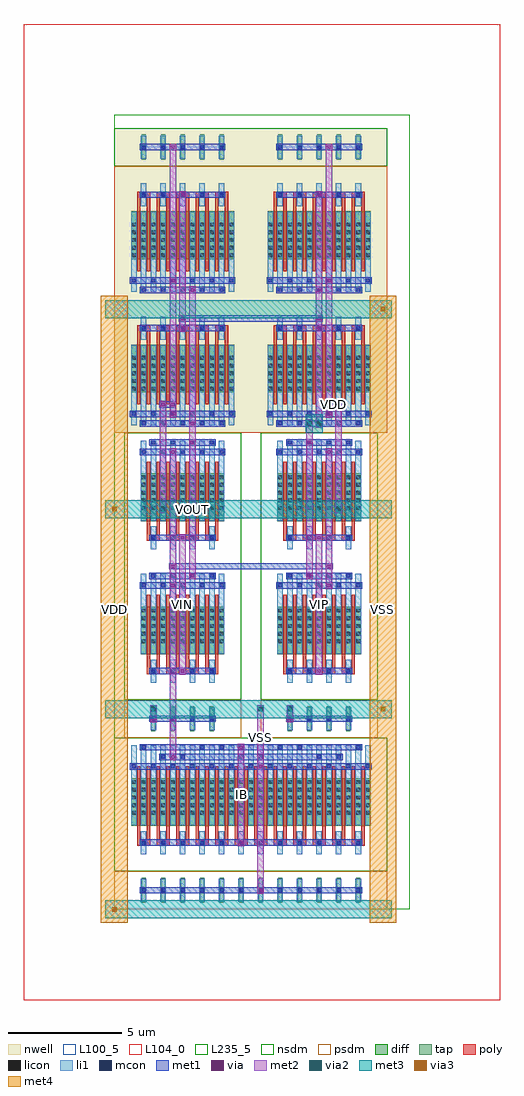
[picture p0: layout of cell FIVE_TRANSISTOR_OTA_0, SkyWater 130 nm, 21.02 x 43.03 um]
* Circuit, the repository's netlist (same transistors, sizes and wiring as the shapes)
* NGSPICE file created from FIVE_TRANSISTOR_OTA_0.ext - technology: sky130A

.subckt DCL_PMOS_S_71268420_X5_Y2_1774869003 a_200_252# w_0_0#
X0 a_200_252# a_200_252# w_0_0# w_0_0# sky130_fd_pr__pfet_01v8 ad=0.294 pd=2.38 as=0.5565 ps=4.73 w=2.1 l=0.15 M=20
.ends

.subckt NMOS_4T_52804903_X4_Y2_1774869004 a_230_357# a_200_252# a_147_357# a_241_2408#
X0 a_230_357# a_200_252# a_147_357# a_241_2408# sky130_fd_pr__nfet_01v8 ad=0.294 pd=2.38 as=0.294 ps=2.38 w=2.1 l=0.15 M=16
.ends

.subckt PMOS_S_5261831_X5_Y2_1774869005 a_230_357# a_200_252# w_0_0#
X0 a_230_357# a_200_252# w_0_0# w_0_0# sky130_fd_pr__pfet_01v8 ad=0.294 pd=2.38 as=0.5565 ps=4.73 w=2.1 l=0.15 M=20
.ends

.subckt SCM_NMOS_9937040_X6_Y1_1774869006 a_200_252# a_402_357# a_147_357#
X0 a_402_357# a_200_252# a_147_357# a_147_357# sky130_fd_pr__nfet_01v8 ad=0.294 pd=2.38 as=0.294 ps=2.38 w=2.1 l=0.15 M=12
X1 a_147_357# a_200_252# a_200_252# a_147_357# sky130_fd_pr__nfet_01v8 ad=0.5565 pd=4.73 as=0.294 ps=2.38 w=2.1 l=0.15 M=12
.ends

.subckt FIVE_TRANSISTOR_OTA_0 IB VOUT VIP VIN VSS VDD
XDCL_PMOS_S_71268420_X5_Y2_1774869003_0 m1_570_5180# VDD DCL_PMOS_S_71268420_X5_Y2_1774869003
XNMOS_4T_52804903_X4_Y2_1774869004_1 m1_570_5180# VIP m1_484_2996# VSS NMOS_4T_52804903_X4_Y2_1774869004
XNMOS_4T_52804903_X4_Y2_1774869004_0 VOUT VIN m1_484_2996# VSS NMOS_4T_52804903_X4_Y2_1774869004
XPMOS_S_5261831_X5_Y2_1774869005_0 VOUT m1_570_5180# VDD PMOS_S_5261831_X5_Y2_1774869005
XSCM_NMOS_9937040_X6_Y1_1774869006_0 IB m1_484_2996# VSS SCM_NMOS_9937040_X6_Y1_1774869006
.ends

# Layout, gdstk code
from math import pi, radians
import gdstk
lib = gdstk.Library(unit=1e-6, precision=1e-09)
def R(c, l, rs):  # rectangles x0, y0, x1, y1
    for r in rs: c.add(gdstk.rectangle(r[:2], r[2:], *l))
def A(c, l, x, y, w, h, nx, ny, dx, dy):  # array of equal rectangles
    R(c, l, [(x+i*dx, y+j*dy, x+i*dx+w, y+j*dy+h) for i in range(nx) for j in range(ny)])
def P(c, l, *ps):  # polygons
    for p in ps: c.add(gdstk.Polygon(p, *l))
nwell = (64, 20)
diff = (65, 20)
tap = (65, 44)
poly = (66, 20)
licon = (66, 44)
li1 = (67, 20)
mcon = (67, 44)
met1 = (68, 20)
via = (68, 44)
met2 = (69, 20)
via2 = (69, 44)
met3 = (70, 20)
via3 = (70, 44)
met4 = (71, 20)
nsdm = (93, 44)
psdm = (94, 20)
L100_5 = (100, 5)
L104_0 = (104, 0)
L235_5 = (235, 5)

scm_nmos_9937040_x6_y1_1 = lib.new_cell('SCM_NMOS_9937040_X6_Y1_1774869006')
R(scm_nmos_9937040_x6_y1_1, diff, [(0.735,1.785,11.305,3.885)])
A(scm_nmos_9937040_x6_y1_1, tap, 1.205, 6.16, 0.17, 1.12, 12, 1, 0.86, 0)
A(scm_nmos_9937040_x6_y1_1, poly, 1, 1.26, 0.15, 3.36, 24, 1, 0.43, 0)
A(scm_nmos_9937040_x6_y1_1, poly, 1, 4.485, 0.58, 0.27, 12, 1, 0.86, 0)
A(scm_nmos_9937040_x6_y1_1, licon, 0.775, 1.865, 0.17, 0.17, 3, 5, 0.43, 0.34)
A(scm_nmos_9937040_x6_y1_1, licon, 1.635, 1.865, 0.17, 0.17, 3, 5, 0.43, 0.34)
A(scm_nmos_9937040_x6_y1_1, licon, 2.495, 1.865, 0.17, 0.17, 3, 5, 0.43, 0.34)
A(scm_nmos_9937040_x6_y1_1, licon, 3.355, 1.865, 0.17, 0.17, 3, 5, 0.43, 0.34)
A(scm_nmos_9937040_x6_y1_1, licon, 4.215, 1.865, 0.17, 0.17, 3, 5, 0.43, 0.34)
A(scm_nmos_9937040_x6_y1_1, licon, 5.075, 1.865, 0.17, 0.17, 3, 5, 0.43, 0.34)
A(scm_nmos_9937040_x6_y1_1, licon, 5.935, 1.865, 0.17, 0.17, 3, 5, 0.43, 0.34)
A(scm_nmos_9937040_x6_y1_1, licon, 6.795, 1.865, 0.17, 0.17, 3, 5, 0.43, 0.34)
A(scm_nmos_9937040_x6_y1_1, licon, 7.655, 1.865, 0.17, 0.17, 3, 5, 0.43, 0.34)
A(scm_nmos_9937040_x6_y1_1, licon, 8.515, 1.865, 0.17, 0.17, 3, 5, 0.43, 0.34)
A(scm_nmos_9937040_x6_y1_1, licon, 9.375, 1.865, 0.17, 0.17, 3, 5, 0.43, 0.34)
A(scm_nmos_9937040_x6_y1_1, licon, 10.235, 1.865, 0.17, 0.17, 3, 5, 0.43, 0.34)
A(scm_nmos_9937040_x6_y1_1, licon, 1.205, 4.535, 0.17, 0.17, 12, 2, 0.86, 2.1)
A(scm_nmos_9937040_x6_y1_1, li1, 0.735, 0.335, 0.25, 3.53, 25, 1, 0.43, 0)
A(scm_nmos_9937040_x6_y1_1, li1, 1.165, 4.115, 0.25, 1.01, 12, 2, 0.86, 2.1)
A(scm_nmos_9937040_x6_y1_1, mcon, 0.775, 1.175, 0.17, 0.17, 13, 1, 0.86, 0)
A(scm_nmos_9937040_x6_y1_1, mcon, 1.205, 4.535, 0.17, 0.17, 12, 2, 0.86, 2.1)
R(scm_nmos_9937040_x6_y1_1, mcon, [(1.205,0.335,1.375,0.505), (3.785,0.335,3.955,0.505), (4.645,0.335,4.815,0.505), (7.225,0.335,7.395,0.505), (8.085,0.335,8.255,0.505), (10.665,0.335,10.835,0.505), (2.065,0.755,2.235,0.925), (2.925,0.755,3.095,0.925), (5.505,0.755,5.675,0.925), (6.365,0.755,6.535,0.925), (8.945,0.755,9.115,0.925), (9.805,0.755,9.975,0.925)])
R(scm_nmos_9937040_x6_y1_1, met1, [(1.12,0.28,10.92,0.56), (1.98,0.7,10.06,0.98), (0.69,1.12,11.35,1.4), (1.12,4.48,10.92,4.76), (1.12,6.58,10.92,6.86)])
R(scm_nmos_9937040_x6_y1_1, via, [(5.515,0.345,5.665,0.495), (6.375,1.185,6.525,1.335), (5.515,4.545,5.665,4.695), (6.375,6.645,6.525,6.795)])
R(scm_nmos_9937040_x6_y1_1, met2, [(5.45,0.26,5.73,4.78), (6.31,1.1,6.59,6.88)])
R(scm_nmos_9937040_x6_y1_1, nsdm, [(0,0,12.04,5.88)])
R(scm_nmos_9937040_x6_y1_1, psdm, [(0,5.88,12.04,7.56)])
R(scm_nmos_9937040_x6_y1_1, L100_5, [(0,0,12.04,7.56)])

dcl_pmos_s_71268420_x5_y = lib.new_cell('DCL_PMOS_S_71268420_X5_Y2_1774869003')
R(dcl_pmos_s_71268420_x5_y, nwell, [(0,0,6.02,13.44)])
R(dcl_pmos_s_71268420_x5_y, diff, [(0.735,1.785,5.285,3.885), (0.735,7.665,5.285,9.765)])
A(dcl_pmos_s_71268420_x5_y, tap, 1.205, 12.04, 0.17, 1.12, 5, 1, 0.86, 0)
A(dcl_pmos_s_71268420_x5_y, poly, 1, 1.26, 0.15, 3.36, 10, 2, 0.43, 5.88)
A(dcl_pmos_s_71268420_x5_y, poly, 1, 4.485, 0.58, 0.27, 5, 2, 0.86, 5.88)
A(dcl_pmos_s_71268420_x5_y, licon, 0.775, 1.865, 0.17, 0.17, 3, 5, 0.43, 0.34)
A(dcl_pmos_s_71268420_x5_y, licon, 1.635, 1.865, 0.17, 0.17, 3, 5, 0.43, 0.34)
A(dcl_pmos_s_71268420_x5_y, licon, 2.495, 1.865, 0.17, 0.17, 3, 5, 0.43, 0.34)
A(dcl_pmos_s_71268420_x5_y, licon, 3.355, 1.865, 0.17, 0.17, 3, 5, 0.43, 0.34)
A(dcl_pmos_s_71268420_x5_y, licon, 4.215, 1.865, 0.17, 0.17, 3, 5, 0.43, 0.34)
A(dcl_pmos_s_71268420_x5_y, licon, 1.205, 4.535, 0.17, 0.17, 5, 2, 0.86, 5.88)
A(dcl_pmos_s_71268420_x5_y, licon, 0.775, 7.745, 0.17, 0.17, 3, 5, 0.43, 0.34)
A(dcl_pmos_s_71268420_x5_y, licon, 1.635, 7.745, 0.17, 0.17, 3, 5, 0.43, 0.34)
A(dcl_pmos_s_71268420_x5_y, licon, 2.495, 7.745, 0.17, 0.17, 3, 5, 0.43, 0.34)
A(dcl_pmos_s_71268420_x5_y, licon, 3.355, 7.745, 0.17, 0.17, 3, 5, 0.43, 0.34)
A(dcl_pmos_s_71268420_x5_y, licon, 4.215, 7.745, 0.17, 0.17, 3, 5, 0.43, 0.34)
R(dcl_pmos_s_71268420_x5_y, licon, [(1.205,12.515,1.375,12.685), (1.205,12.515,1.375,12.685), (2.065,12.515,2.235,12.685), (2.065,12.515,2.235,12.685), (2.925,12.515,3.095,12.685), (2.925,12.515,3.095,12.685), (3.785,12.515,3.955,12.685), (3.785,12.515,3.955,12.685), (4.645,12.515,4.815,12.685), (4.645,12.515,4.815,12.685)])
A(dcl_pmos_s_71268420_x5_y, li1, 0.735, 0.335, 0.25, 3.53, 11, 2, 0.43, 5.88)
A(dcl_pmos_s_71268420_x5_y, li1, 1.165, 4.115, 0.25, 1.01, 5, 2, 0.86, 5.88)
A(dcl_pmos_s_71268420_x5_y, li1, 1.165, 12.095, 0.25, 1.01, 5, 1, 0.86, 0)
A(dcl_pmos_s_71268420_x5_y, mcon, 1.205, 0.335, 0.17, 0.17, 5, 2, 0.86, 4.2)
A(dcl_pmos_s_71268420_x5_y, mcon, 0.775, 0.755, 0.17, 0.17, 6, 2, 0.86, 5.88)
A(dcl_pmos_s_71268420_x5_y, mcon, 1.205, 6.215, 0.17, 0.17, 5, 2, 0.86, 4.2)
A(dcl_pmos_s_71268420_x5_y, mcon, 1.205, 12.515, 0.17, 0.17, 5, 1, 0.86, 0)
R(dcl_pmos_s_71268420_x5_y, met1, [(1.12,0.28,4.9,0.56), (0.69,0.7,5.33,0.98), (1.12,4.48,4.9,4.76), (1.12,6.16,4.9,6.44), (0.69,6.58,5.33,6.86), (1.12,10.36,4.9,10.64), (1.12,12.46,4.9,12.74)])
A(dcl_pmos_s_71268420_x5_y, via, 3.365, 0.765, 0.15, 0.15, 1, 3, 0, 5.88)
R(dcl_pmos_s_71268420_x5_y, via, [(2.935,0.345,3.085,0.495), (2.935,4.545,3.085,4.695), (2.935,6.225,3.085,6.375), (2.935,10.425,3.085,10.575)])
R(dcl_pmos_s_71268420_x5_y, met2, [(2.87,0.26,3.15,10.66), (3.3,0.68,3.58,12.76)])
R(dcl_pmos_s_71268420_x5_y, nsdm, [(0,11.76,6.02,13.44)])
R(dcl_pmos_s_71268420_x5_y, psdm, [(0,0,6.02,11.76)])
R(dcl_pmos_s_71268420_x5_y, L100_5, [(0,0,6.02,13.44)])

pmos_s_5261831_x5_y2_177 = lib.new_cell('PMOS_S_5261831_X5_Y2_1774869005')
R(pmos_s_5261831_x5_y2_177, nwell, [(0,0,6.02,13.44)])
R(pmos_s_5261831_x5_y2_177, diff, [(0.735,1.785,5.285,3.885), (0.735,7.665,5.285,9.765)])
A(pmos_s_5261831_x5_y2_177, tap, 1.205, 12.04, 0.17, 1.12, 5, 1, 0.86, 0)
A(pmos_s_5261831_x5_y2_177, poly, 1, 1.26, 0.15, 3.36, 10, 2, 0.43, 5.88)
A(pmos_s_5261831_x5_y2_177, poly, 1, 4.485, 0.58, 0.27, 5, 2, 0.86, 5.88)
A(pmos_s_5261831_x5_y2_177, licon, 0.775, 1.865, 0.17, 0.17, 3, 5, 0.43, 0.34)
A(pmos_s_5261831_x5_y2_177, licon, 1.635, 1.865, 0.17, 0.17, 3, 5, 0.43, 0.34)
A(pmos_s_5261831_x5_y2_177, licon, 2.495, 1.865, 0.17, 0.17, 3, 5, 0.43, 0.34)
A(pmos_s_5261831_x5_y2_177, licon, 3.355, 1.865, 0.17, 0.17, 3, 5, 0.43, 0.34)
A(pmos_s_5261831_x5_y2_177, licon, 4.215, 1.865, 0.17, 0.17, 3, 5, 0.43, 0.34)
A(pmos_s_5261831_x5_y2_177, licon, 1.205, 4.535, 0.17, 0.17, 5, 2, 0.86, 5.88)
A(pmos_s_5261831_x5_y2_177, licon, 0.775, 7.745, 0.17, 0.17, 3, 5, 0.43, 0.34)
A(pmos_s_5261831_x5_y2_177, licon, 1.635, 7.745, 0.17, 0.17, 3, 5, 0.43, 0.34)
A(pmos_s_5261831_x5_y2_177, licon, 2.495, 7.745, 0.17, 0.17, 3, 5, 0.43, 0.34)
A(pmos_s_5261831_x5_y2_177, licon, 3.355, 7.745, 0.17, 0.17, 3, 5, 0.43, 0.34)
A(pmos_s_5261831_x5_y2_177, licon, 4.215, 7.745, 0.17, 0.17, 3, 5, 0.43, 0.34)
R(pmos_s_5261831_x5_y2_177, licon, [(1.205,12.515,1.375,12.685), (1.205,12.515,1.375,12.685), (2.065,12.515,2.235,12.685), (2.065,12.515,2.235,12.685), (2.925,12.515,3.095,12.685), (2.925,12.515,3.095,12.685), (3.785,12.515,3.955,12.685), (3.785,12.515,3.955,12.685), (4.645,12.515,4.815,12.685), (4.645,12.515,4.815,12.685)])
A(pmos_s_5261831_x5_y2_177, li1, 0.735, 0.335, 0.25, 3.53, 11, 2, 0.43, 5.88)
A(pmos_s_5261831_x5_y2_177, li1, 1.165, 4.115, 0.25, 1.01, 5, 2, 0.86, 5.88)
A(pmos_s_5261831_x5_y2_177, li1, 1.165, 12.095, 0.25, 1.01, 5, 1, 0.86, 0)
A(pmos_s_5261831_x5_y2_177, mcon, 1.205, 0.335, 0.17, 0.17, 5, 2, 0.86, 4.2)
A(pmos_s_5261831_x5_y2_177, mcon, 0.775, 0.755, 0.17, 0.17, 6, 2, 0.86, 5.88)
A(pmos_s_5261831_x5_y2_177, mcon, 1.205, 6.215, 0.17, 0.17, 5, 2, 0.86, 4.2)
A(pmos_s_5261831_x5_y2_177, mcon, 1.205, 12.515, 0.17, 0.17, 5, 1, 0.86, 0)
R(pmos_s_5261831_x5_y2_177, met1, [(1.12,0.28,4.9,0.56), (0.69,0.7,5.33,0.98), (1.12,4.48,4.9,4.76), (1.12,6.16,4.9,6.44), (0.69,6.58,5.33,6.86), (1.12,10.36,4.9,10.64), (1.12,12.46,4.9,12.74)])
A(pmos_s_5261831_x5_y2_177, via, 3.365, 0.765, 0.15, 0.15, 1, 3, 0, 5.88)
R(pmos_s_5261831_x5_y2_177, via, [(2.505,0.345,2.655,0.495), (2.935,4.545,3.085,4.695), (2.505,6.225,2.655,6.375), (2.935,10.425,3.085,10.575)])
R(pmos_s_5261831_x5_y2_177, met2, [(2.44,0.26,2.72,6.46), (3.3,0.68,3.58,12.76), (2.87,4.46,3.15,10.66)])
R(pmos_s_5261831_x5_y2_177, nsdm, [(0,11.76,6.02,13.44)])
R(pmos_s_5261831_x5_y2_177, psdm, [(0,0,6.02,11.76)])
R(pmos_s_5261831_x5_y2_177, L100_5, [(0,0,6.02,13.44)])

nmos_4t_52804903_x4_y2_1 = lib.new_cell('NMOS_4T_52804903_X4_Y2_1774869004')
R(nmos_4t_52804903_x4_y2_1, diff, [(0.735,1.785,4.425,3.885), (0.735,7.665,4.425,9.765)])
A(nmos_4t_52804903_x4_y2_1, tap, 1.205, 12.04, 0.17, 1.12, 4, 1, 0.86, 0)
A(nmos_4t_52804903_x4_y2_1, poly, 1, 1.26, 0.15, 3.36, 8, 2, 0.43, 5.88)
A(nmos_4t_52804903_x4_y2_1, poly, 1, 4.485, 0.58, 0.27, 4, 2, 0.86, 5.88)
A(nmos_4t_52804903_x4_y2_1, licon, 0.775, 1.865, 0.17, 0.17, 3, 5, 0.43, 0.34)
A(nmos_4t_52804903_x4_y2_1, licon, 1.635, 1.865, 0.17, 0.17, 3, 5, 0.43, 0.34)
A(nmos_4t_52804903_x4_y2_1, licon, 2.495, 1.865, 0.17, 0.17, 3, 5, 0.43, 0.34)
A(nmos_4t_52804903_x4_y2_1, licon, 3.355, 1.865, 0.17, 0.17, 3, 5, 0.43, 0.34)
A(nmos_4t_52804903_x4_y2_1, licon, 1.205, 4.535, 0.17, 0.17, 4, 2, 0.86, 5.88)
A(nmos_4t_52804903_x4_y2_1, licon, 0.775, 7.745, 0.17, 0.17, 3, 5, 0.43, 0.34)
A(nmos_4t_52804903_x4_y2_1, licon, 1.635, 7.745, 0.17, 0.17, 3, 5, 0.43, 0.34)
A(nmos_4t_52804903_x4_y2_1, licon, 2.495, 7.745, 0.17, 0.17, 3, 5, 0.43, 0.34)
A(nmos_4t_52804903_x4_y2_1, licon, 3.355, 7.745, 0.17, 0.17, 3, 5, 0.43, 0.34)
R(nmos_4t_52804903_x4_y2_1, licon, [(1.205,12.515,1.375,12.685), (1.205,12.515,1.375,12.685), (2.065,12.515,2.235,12.685), (2.065,12.515,2.235,12.685), (2.925,12.515,3.095,12.685), (2.925,12.515,3.095,12.685), (3.785,12.515,3.955,12.685), (3.785,12.515,3.955,12.685)])
A(nmos_4t_52804903_x4_y2_1, li1, 0.735, 0.335, 0.25, 3.53, 9, 2, 0.43, 5.88)
A(nmos_4t_52804903_x4_y2_1, li1, 1.165, 4.115, 0.25, 1.01, 4, 2, 0.86, 5.88)
A(nmos_4t_52804903_x4_y2_1, li1, 1.165, 12.095, 0.25, 1.01, 4, 1, 0.86, 0)
A(nmos_4t_52804903_x4_y2_1, mcon, 1.205, 0.335, 0.17, 0.17, 4, 2, 0.86, 4.2)
A(nmos_4t_52804903_x4_y2_1, mcon, 0.775, 0.755, 0.17, 0.17, 5, 2, 0.86, 5.88)
A(nmos_4t_52804903_x4_y2_1, mcon, 1.205, 6.215, 0.17, 0.17, 4, 2, 0.86, 4.2)
A(nmos_4t_52804903_x4_y2_1, mcon, 1.205, 12.515, 0.17, 0.17, 4, 1, 0.86, 0)
R(nmos_4t_52804903_x4_y2_1, met1, [(1.12,0.28,4.04,0.56), (0.69,0.7,4.47,0.98), (1.12,4.48,4.04,4.76), (1.12,6.16,4.04,6.44), (0.69,6.58,4.47,6.86), (1.12,10.36,4.04,10.64), (1.12,12.46,4.04,12.74)])
R(nmos_4t_52804903_x4_y2_1, via, [(2.075,0.345,2.225,0.495), (2.935,0.765,3.085,0.915), (2.505,4.545,2.655,4.695), (2.075,6.225,2.225,6.375), (2.935,6.645,3.085,6.795), (2.505,10.425,2.655,10.575)])
R(nmos_4t_52804903_x4_y2_1, met2, [(2.01,0.26,2.29,6.46), (2.87,0.68,3.15,6.88), (2.44,4.46,2.72,10.66)])
R(nmos_4t_52804903_x4_y2_1, nsdm, [(0,0,5.16,11.76)])
R(nmos_4t_52804903_x4_y2_1, psdm, [(0,11.76,5.16,13.44)])
R(nmos_4t_52804903_x4_y2_1, L100_5, [(0,0,5.16,13.44)])

five_transistor_ota_0 = lib.new_cell('FIVE_TRANSISTOR_OTA_0')
R(five_transistor_ota_0, met1, [(2.42,6.58,2.74,6.86), (2.42,6.58,2.74,6.86), (2.42,6.58,2.74,6.86), (2.42,6.58,2.74,6.86), (1.56,8.26,1.88,8.54), (1.56,8.26,1.88,8.54), (7.58,8.26,7.9,8.54), (7.58,8.26,7.9,8.54), (7.58,8.26,7.9,8.54), (2.42,14.98,2.74,15.26), (2.42,14.98,2.74,15.26), (2.58,14.98,9.46,15.26), (9.3,14.98,9.62,15.26), (9.3,14.98,9.62,15.26), (1.99,22.12,2.31,22.4), (1.99,22.12,2.31,22.4), (2.15,22.12,2.58,22.4), (2.42,22.12,2.74,22.4), (2.42,22.12,2.74,22.4), (9.3,22.12,9.62,22.4), (9.3,22.12,9.62,22.4), (9.3,22.12,9.62,22.4), (9.46,22.12,9.89,22.4), (9.73,22.12,10.05,22.4), (9.73,22.12,10.05,22.4), (9.73,22.12,10.05,22.4), (2.85,25.9,3.17,26.18), (2.85,25.9,3.17,26.18), (3.01,25.9,9.03,26.18), (8.87,25.9,9.19,26.18), (8.87,25.9,9.19,26.18)])
P(five_transistor_ota_0, met1, [(0,0),(0,0),(0,0),(0,0)],
  [(0,0),(0,0),(0,0),(0,0)],
  [(0,0),(0,0),(0,0),(0,0)])
R(five_transistor_ota_0, via, [(2.505,6.645,2.655,6.795), (2.505,6.645,2.655,6.795), (2.505,6.645,2.655,6.795), (2.505,6.645,2.655,6.795), (1.645,8.325,1.795,8.475), (1.645,8.325,1.795,8.475), (7.665,8.325,7.815,8.475), (7.665,8.325,7.815,8.475), (7.665,8.325,7.815,8.475), (2.505,15.045,2.655,15.195), (2.505,15.045,2.655,15.195), (9.385,15.045,9.535,15.195), (9.385,15.045,9.535,15.195), (2.075,22.185,2.225,22.335), (2.075,22.185,2.225,22.335), (2.505,22.185,2.655,22.335), (2.505,22.185,2.655,22.335), (9.385,22.185,9.535,22.335), (9.385,22.185,9.535,22.335), (9.385,22.185,9.535,22.335), (9.815,22.185,9.965,22.335), (9.815,22.185,9.965,22.335), (9.815,22.185,9.965,22.335), (2.935,25.965,3.085,26.115), (2.935,25.965,3.085,26.115), (8.955,25.965,9.105,26.115), (8.955,25.965,9.105,26.115)])
R(five_transistor_ota_0, met2, [(6.31,6.3,6.59,8.82), (2.44,6.56,2.72,6.88), (2.44,6.56,2.72,6.88), (2.44,6.56,2.72,6.88), (2.44,6.56,2.72,6.88), (2.44,6.72,2.72,14.28), (1.58,8.24,1.86,8.56), (1.58,8.24,1.86,8.56), (7.6,8.24,7.88,8.56), (7.6,8.24,7.88,8.56), (7.6,8.24,7.88,8.56), (1.58,8.4,1.86,8.82), (7.6,8.4,7.88,8.82), (1.58,8.635,1.86,9.005), (1.58,8.635,1.86,9.005), (6.31,8.635,6.59,9.005), (6.31,8.635,6.59,9.005), (6.31,8.635,6.59,9.005), (6.31,8.635,6.59,9.005), (7.6,8.635,7.88,9.005), (7.6,8.635,7.88,9.005), (7.6,8.635,7.88,9.005), (2.44,14.96,2.72,15.28), (2.44,14.96,2.72,15.28), (9.32,14.96,9.6,15.28), (9.32,14.96,9.6,15.28), (2.01,17.455,2.29,17.825), (2.01,17.455,2.29,17.825), (9.75,17.455,10.03,17.825), (9.75,17.455,10.03,17.825), (9.75,17.455,10.03,17.825), (2.01,17.64,2.29,22.26), (9.75,17.64,10.03,22.26), (3.3,20.58,3.58,21.42), (8.46,20.58,8.74,21.42), (8.46,21.235,8.74,21.605), (8.46,21.235,8.74,21.605), (8.46,21.235,8.74,21.605), (8.46,21.235,8.74,21.605), (8.89,21.235,9.17,21.605), (8.89,21.235,9.17,21.605), (8.89,21.235,9.17,21.605), (8.89,21.235,9.17,21.605), (2.01,22.1,2.29,22.42), (2.01,22.1,2.29,22.42), (2.44,22.1,2.72,22.42), (2.44,22.1,2.72,22.42), (9.32,22.1,9.6,22.42), (9.32,22.1,9.6,22.42), (9.32,22.1,9.6,22.42), (9.75,22.1,10.03,22.42), (9.75,22.1,10.03,22.42), (9.75,22.1,10.03,22.42), (2.87,25.88,3.15,26.2), (2.87,25.88,3.15,26.2), (8.89,25.88,9.17,26.2), (8.89,25.88,9.17,26.2)])
P(five_transistor_ota_0, met2, [(0,0),(0,0),(0,0),(0,0)],
  [(0,0),(0,0),(0,0),(0,0)],
  [(0,0),(0,0),(0,0),(0,0)],
  [(0,0),(0,0),(0,0),(0,0)],
  [(0,0),(0,0),(0,0),(0,0)],
  [(0,0),(0,0),(0,0),(0,0)],
  [(0,0),(0,0),(0,0),(0,0)],
  [(0,0),(0,0),(0,0),(0,0)],
  [(0,0),(0,0),(0,0),(0,0)],
  [(0,0),(0,0),(0,0),(0,0)],
  [(0,0),(0,0),(0,0),(0,0)],
  [(0,0),(0,0),(0,0),(0,0)],
  [(0,0),(0,0),(0,0),(0,0)],
  [(0,0),(0,0),(0,0),(0,0)],
  [(0,0),(0,0),(0,0),(0,0)],
  [(0,0),(0,0),(0,0),(0,0)],
  [(0,0),(0,0),(0,0),(0,0)])
R(five_transistor_ota_0, via2, [(1.62,8.72,1.82,8.92), (1.62,8.72,1.82,8.92), (6.35,8.72,6.55,8.92), (6.35,8.72,6.55,8.92), (6.35,8.72,6.55,8.92), (6.35,8.72,6.55,8.92), (7.64,8.72,7.84,8.92), (7.64,8.72,7.84,8.92), (7.64,8.72,7.84,8.92), (2.05,17.54,2.25,17.74), (2.05,17.54,2.25,17.74), (9.79,17.54,9.99,17.74), (9.79,17.54,9.99,17.74), (9.79,17.54,9.99,17.74), (8.5,21.32,8.7,21.52), (8.5,21.32,8.7,21.52), (8.5,21.32,8.7,21.52), (8.5,21.32,8.7,21.52), (8.93,21.32,9.13,21.52), (8.93,21.32,9.13,21.52), (8.93,21.32,9.13,21.52), (8.93,21.32,9.13,21.52)])
A(five_transistor_ota_0, met3, -0.4, -0.4, 4.24, 0.8, 3, 4, 3.44, 8.82)
A(five_transistor_ota_0, met3, 9.92, -0.4, 2.32, 0.8, 1, 4, 0, 8.82)
R(five_transistor_ota_0, met3, [(-0.165,-0.4,0.165,0.4), (1.555,8.42,1.885,9.22), (1.555,8.42,1.885,9.22), (6.285,8.42,6.615,9.22), (6.285,8.42,6.615,9.22), (6.285,8.42,6.615,9.22), (6.285,8.42,6.615,9.22), (7.575,8.42,7.905,9.22), (7.575,8.42,7.905,9.22), (7.575,8.42,7.905,9.22), (11.675,8.42,12.005,9.22), (-0.165,17.24,0.165,18.04), (1.985,17.24,2.315,18.04), (1.985,17.24,2.315,18.04), (9.725,17.24,10.055,18.04), (9.725,17.24,10.055,18.04), (9.725,17.24,10.055,18.04), (8.435,21.02,8.765,21.82), (8.435,21.02,8.765,21.82), (8.435,21.02,8.765,21.82), (8.435,21.02,8.765,21.82), (8.6,21.02,9.03,21.82), (8.865,21.02,9.195,21.82), (8.865,21.02,9.195,21.82), (8.865,21.02,9.195,21.82), (8.865,21.02,9.195,21.82), (11.675,26.06,12.005,26.86)])
R(five_transistor_ota_0, via3, [(-0.1,-0.1,0.1,0.1), (11.74,8.72,11.94,8.92), (-0.1,17.54,0.1,17.74), (11.74,26.36,11.94,26.56)])
A(five_transistor_ota_0, met4, -0.59, -0.59, 1.18, 10, 1, 3, 0, 8.82)
A(five_transistor_ota_0, met4, 11.25, -0.59, 1.18, 10, 1, 3, 0, 8.82)
R(five_transistor_ota_0, met4, [(-0.59,-0.165,0.59,0.165), (11.25,8.655,12.43,8.985), (-0.59,17.475,0.59,17.805), (11.25,26.295,12.43,26.625)])
R(five_transistor_ota_0, L104_0, [(-4,-4,17.02,39.03)])
R(five_transistor_ota_0, L235_5, [(0,0,13.02,35.03)])
five_transistor_ota_0.add(gdstk.Reference(scm_nmos_9937040_x6_y1_1, (0,7.56), x_reflection=True))
five_transistor_ota_0.add(gdstk.Reference(dcl_pmos_s_71268420_x5_y, (6.02,21)))
five_transistor_ota_0.add(gdstk.Reference(pmos_s_5261831_x5_y2_177, (6.02,21), rotation=pi, x_reflection=True))
five_transistor_ota_0.add(gdstk.Reference(nmos_4t_52804903_x4_y2_1, (6.45,21), x_reflection=True))
five_transistor_ota_0.add(gdstk.Reference(nmos_4t_52804903_x4_y2_1, (5.59,21), rotation=pi))
five_transistor_ota_0.add(gdstk.Label('IB', (5.59,5.04), layer=69, texttype=5))
five_transistor_ota_0.add(gdstk.Label('VOUT', (3.44,17.64), layer=69, texttype=5))
five_transistor_ota_0.add(gdstk.Label('VIP', (9.03,13.44), layer=69, texttype=5))
five_transistor_ota_0.add(gdstk.Label('VIN', (3.01,13.44), layer=69, texttype=5))
five_transistor_ota_0.add(gdstk.Label('VSS', (6.45,7.56), layer=69, texttype=5))
five_transistor_ota_0.add(gdstk.Label('VSS', (11.84,13.23), layer=71, texttype=5))
five_transistor_ota_0.add(gdstk.Label('VSS', (11.84,13.23), layer=71, texttype=5))
five_transistor_ota_0.add(gdstk.Label('VSS', (11.84,13.23), layer=71, texttype=5))
five_transistor_ota_0.add(gdstk.Label('VSS', (11.84,13.23), layer=71, texttype=5))
five_transistor_ota_0.add(gdstk.Label('VSS', (11.84,13.23), layer=71, texttype=5))
five_transistor_ota_0.add(gdstk.Label('VSS', (11.84,13.23), layer=71, texttype=5))
five_transistor_ota_0.add(gdstk.Label('VSS', (11.84,13.23), layer=71, texttype=5))
five_transistor_ota_0.add(gdstk.Label('VSS', (11.84,13.23), layer=71, texttype=5))
five_transistor_ota_0.add(gdstk.Label('VDD', (0,13.23), layer=71, texttype=5))
five_transistor_ota_0.add(gdstk.Label('VDD', (9.675,22.26), layer=68, texttype=5))
five_transistor_ota_0.add(gdstk.Label('VDD', (0,13.23), layer=71, texttype=5))
five_transistor_ota_0.add(gdstk.Label('VDD', (0,13.23), layer=71, texttype=5))
five_transistor_ota_0.add(gdstk.Label('VDD', (0,13.23), layer=71, texttype=5))
five_transistor_ota_0.add(gdstk.Label('VDD', (0,13.23), layer=71, texttype=5))
five_transistor_ota_0.add(gdstk.Label('VDD', (0,13.23), layer=71, texttype=5))
five_transistor_ota_0.add(gdstk.Label('VDD', (0,13.23), layer=71, texttype=5))
five_transistor_ota_0.add(gdstk.Label('VDD', (0,13.23), layer=71, texttype=5))

lib.write_gds('FIVE_TRANSISTOR_OTA_0.gds')
